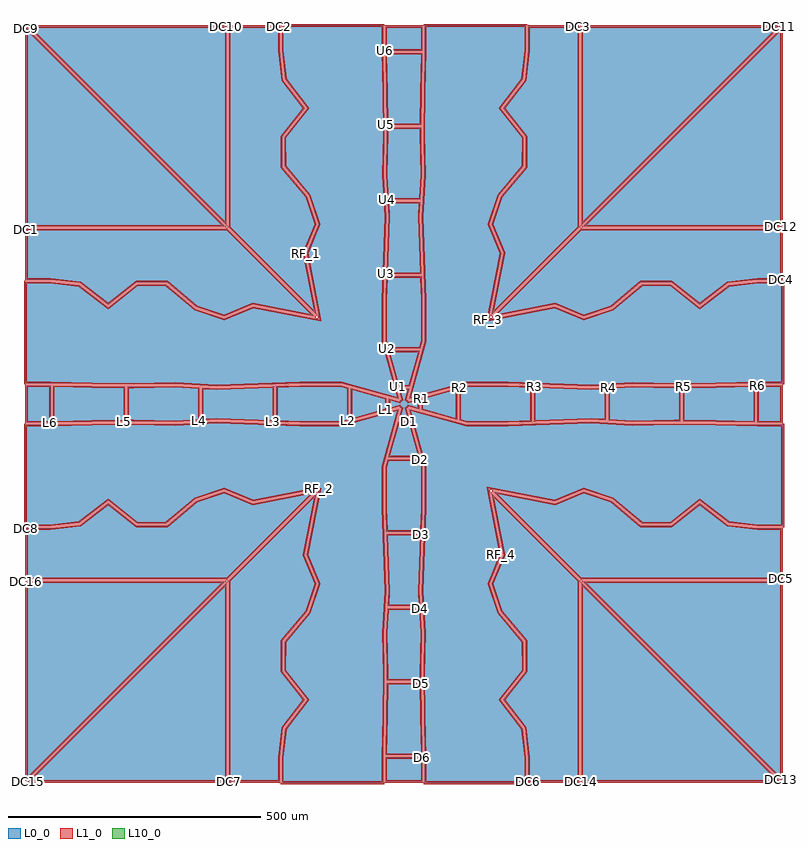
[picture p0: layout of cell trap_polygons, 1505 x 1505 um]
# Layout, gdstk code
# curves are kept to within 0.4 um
import gdstk
lib = gdstk.Library(unit=1e-6, precision=1e-09)
def P(c, l, *ps):  # polygons
    for p in ps: c.add(gdstk.Polygon(p, *l))
L0_0 = (0, 0)
L1_0 = (1, 0)
L10_0 = (10, 0)

trap_polygons = lib.new_cell('trap_polygons')
P(trap_polygons, L0_0, [(-747.5,-351.5),(-355.036,-351.5),(-747.5,-743.964),(-747.5,-351.5)],
  [(-743.964,-747.5),(-351.5,-355.036),(-351.5,-747.5),(-743.964,-747.5)],
  [(351.5,-747.5),(351.5,-355.036),(743.964,-747.5),(351.5,-747.5)],
  [(747.5,-743.964),(355.036,-351.5),(747.5,-351.5),(747.5,-743.964)],
  [(747.5,351.5),(355.036,351.5),(747.5,743.964),(747.5,351.5)],
  [(743.964,747.5),(351.5,355.036),(351.5,747.5),(743.964,747.5)],
  [(-351.5,747.5),(-351.5,355.036),(-743.964,747.5),(-351.5,747.5)],
  [(-747.5,743.964),(-355.036,351.5),(-747.5,351.5),(-747.5,743.964)],
  [(-747.5,-246.5),(-699.71,-246.5),(-640.731,-239.63),(-585.43,-196.951),(-529.805,-241.432),(-468.92,-241.136),(-410.94,-192.501),(-356.299,-173.873),(-299.337,-197.523),(-177.273,-173.737),(-350.036,-346.5),(-747.5,-346.5)],
  [(-346.5,-747.5),(-346.5,-350.036),(-173.737,-177.273),(-197.523,-299.337),(-173.873,-356.299),(-192.501,-410.94),(-241.136,-468.92),(-241.432,-529.805),(-196.951,-585.43),(-239.63,-640.731),(-246.5,-699.71),(-246.5,-747.5)],
  [(246.5,-747.5),(246.5,-699.71),(239.63,-640.731),(196.951,-585.43),(241.432,-529.805),(241.136,-468.92),(192.501,-410.94),(173.873,-356.299),(197.523,-299.337),(173.737,-177.273),(346.5,-350.036),(346.5,-747.5)],
  [(747.5,-346.5),(350.036,-346.5),(177.273,-173.737),(299.337,-197.523),(356.299,-173.873),(410.94,-192.501),(468.92,-241.136),(529.805,-241.432),(585.43,-196.951),(640.731,-239.63),(699.71,-246.5),(747.5,-246.5)],
  [(747.5,246.5),(699.71,246.5),(640.731,239.63),(585.43,196.951),(529.805,241.432),(468.92,241.136),(410.94,192.501),(356.299,173.873),(299.337,197.523),(177.273,173.737),(350.036,346.5),(747.5,346.5)],
  [(346.5,747.5),(346.5,350.036),(173.737,177.273),(197.523,299.337),(173.873,356.299),(192.501,410.94),(241.136,468.92),(241.432,529.805),(196.951,585.43),(239.63,640.731),(246.5,699.71),(246.5,747.5)],
  [(-246.5,747.5),(-246.5,699.71),(-239.63,640.731),(-196.951,585.43),(-241.432,529.805),(-241.136,468.92),(-192.501,410.94),(-173.873,356.299),(-197.523,299.337),(-173.737,177.273),(-346.5,350.036),(-346.5,747.5)],
  [(-747.5,346.5),(-350.036,346.5),(-177.273,173.737),(-299.337,197.523),(-356.299,173.873),(-410.94,192.501),(-468.92,241.136),(-529.805,241.432),(-585.43,196.951),(-640.731,239.63),(-699.71,246.5),(-747.5,246.5)],
  [(-36.5,700),(-36.5,747.5),(36.5,747.5),(36.5,700),(-36.5,700)],
  [(700,36.5),(747.5,36.5),(747.5,-36.5),(700,-36.5),(700,36.5)],
  [(36.5,-700),(36.5,-747.5),(-36.5,-747.5),(-36.5,-700),(36.5,-700)],
  [(-700,-36.5),(-747.5,-36.5),(-747.5,36.5),(-700,36.5),(-700,-36.5)],
  [(-33.917,552.5),(-34.849,617.925),(-36.5,695),(36.5,695),(34.849,617.925),(33.917,552.5),(-33.917,552.5)],
  [(552.5,33.917),(617.925,34.849),(695,36.5),(695,-36.5),(617.925,-34.849),(552.5,-33.917),(552.5,33.917)],
  [(33.917,-552.5),(34.849,-617.925),(36.5,-695),(-36.5,-695),(-34.849,-617.925),(-33.917,-552.5),(33.917,-552.5)],
  [(-552.5,-33.917),(-617.925,-34.849),(-695,-36.5),(-695,36.5),(-617.925,34.849),(-552.5,33.917),(-552.5,-33.917)],
  [(-32.503,405),(-35.298,453.158),(-33.673,535.361),(-33.846,547.5),(33.846,547.5),(33.673,535.361),(35.298,453.158),(32.503,405),(-32.503,405)],
  [(405,32.503),(453.158,35.298),(535.361,33.673),(547.5,33.846),(547.5,-33.846),(535.361,-33.673),(453.158,-35.298),(405,-32.503),(405,32.503)],
  [(32.503,-405),(35.298,-453.158),(33.673,-535.361),(33.846,-547.5),(-33.846,-547.5),(-33.673,-535.361),(-35.298,-453.158),(-32.503,-405),(32.503,-405)],
  [(-405,-32.503),(-453.158,-35.298),(-535.361,-33.673),(-547.5,-33.846),(-547.5,33.846),(-535.361,33.673),(-453.158,35.298),(-405,32.503),(-405,-32.503)],
  [(-34.587,257.5),(-33.444,288.256),(-30.519,370.806),(-32.213,400),(32.213,400),(30.519,370.806),(33.444,288.256),(34.587,257.5),(-34.587,257.5)],
  [(257.5,34.587),(288.256,33.444),(370.806,30.519),(400,32.213),(400,-32.213),(370.806,-30.519),(288.256,-33.444),(257.5,-34.587),(257.5,34.587)],
  [(34.587,-257.5),(33.444,-288.256),(30.519,-370.806),(32.213,-400),(-32.213,-400),(-30.519,-370.806),(-33.444,-288.256),(-34.587,-257.5),(34.587,-257.5)],
  [(-257.5,-34.587),(-288.256,-33.444),(-370.806,-30.519),(-400,-32.213),(-400,32.213),(-370.806,30.519),(-288.256,33.444),(-257.5,34.587),(-257.5,-34.587)],
  [(-32.49,110),(-36.5,124.492),(-36.5,206.032),(-34.773,252.5),(34.773,252.5),(36.5,206.032),(36.5,124.492),(32.49,110),(-32.49,110)],
  [(110,32.49),(124.492,36.5),(206.032,36.5),(252.5,34.773),(252.5,-34.773),(206.032,-36.5),(124.492,-36.5),(110,-32.49),(110,32.49)],
  [(32.49,-110),(36.5,-124.492),(36.5,-206.032),(34.773,-252.5),(-34.773,-252.5),(-36.5,-206.032),(-36.5,-124.492),(-32.49,-110),(32.49,-110)],
  [(-110,-32.49),(-124.492,-36.5),(-206.032,-36.5),(-252.5,-34.773),(-252.5,34.773),(-206.032,36.5),(-124.492,36.5),(-110,32.49),(-110,-32.49)],
  [(-11.734,35),(-31.106,105),(31.106,105),(11.734,35),(-11.734,35)],
  [(35,11.734),(105,31.106),(105,-31.106),(35,-11.734),(35,11.734)],
  [(11.734,-35),(31.106,-105),(-31.106,-105),(-11.734,-35),(11.734,-35)],
  [(-35,-11.734),(-105,-31.106),(-105,31.106),(-35,11.734),(-35,-11.734)],
  [(8.315,-5.556),(4.514,-8.914),(10.35,-30),(-10.35,-30),(-4.514,-8.914),(-7.071,-7.071),(-8.914,-4.514),(-30,-10.35),(-30,10.35),(-8.914,4.514),(-7.071,7.071),(-4.514,8.914),(-10.35,30),(10.35,30),(4.514,8.914),(7.071,7.071),(8.914,4.514),(30,10.35),(30,-10.35),(8.914,-4.514)],
  [(192.327,-298.812),(168.531,-356.125),(188.07,-413.437),(236.144,-470.75),(236.423,-528.062),(190.593,-585.375),(234.824,-642.687),(241.5,-700),(241.5,-750),(41.5,-750),(41.5,-700),(38.674,-535.375),(40.301,-453.062),(35.524,-370.75),(41.5,-206.125),(41.5,-123.812),(10.004,-10.004),(123.812,-41.5),(206.125,-41.5),(370.75,-35.524),(453.062,-40.301),(535.375,-38.674),(700,-41.5),(750,-41.5),(750,-241.5),(700,-241.5),(642.687,-234.824),(585.375,-190.593),(528.062,-236.423),(470.75,-236.144),(413.437,-188.07),(356.125,-168.531),(298.812,-192.327),(166.555,-166.555)],
  [(166.555,166.555),(298.812,192.327),(356.125,168.531),(413.437,188.07),(470.75,236.144),(528.062,236.423),(585.375,190.593),(642.687,234.824),(700,241.5),(750,241.5),(750,41.5),(700,41.5),(535.375,38.674),(453.062,40.301),(370.75,35.524),(206.125,41.5),(123.812,41.5),(10.004,10.004),(41.5,123.812),(41.5,206.125),(35.524,370.75),(40.301,453.062),(38.674,535.375),(41.5,700),(41.5,750),(241.5,750),(241.5,700),(234.824,642.687),(190.593,585.375),(236.423,528.062),(236.144,470.75),(188.07,413.437),(168.531,356.125),(192.327,298.812)],
  [(-166.555,-166.555),(-298.812,-192.327),(-356.125,-168.531),(-413.437,-188.07),(-470.75,-236.144),(-528.062,-236.423),(-585.375,-190.593),(-642.687,-234.824),(-700,-241.5),(-750,-241.5),(-750,-41.5),(-700,-41.5),(-535.375,-38.674),(-453.062,-40.301),(-370.75,-35.524),(-206.125,-41.5),(-123.812,-41.5),(-10.004,-10.004),(-41.5,-123.812),(-41.5,-206.125),(-35.524,-370.75),(-40.301,-453.062),(-38.674,-535.375),(-41.5,-700),(-41.5,-750),(-241.5,-750),(-241.5,-700),(-234.824,-642.687),(-190.593,-585.375),(-236.423,-528.062),(-236.144,-470.75),(-188.07,-413.437),(-168.531,-356.125),(-192.327,-298.812)],
  [(-192.327,298.812),(-168.531,356.125),(-188.07,413.437),(-236.144,470.75),(-236.423,528.062),(-190.593,585.375),(-234.824,642.687),(-241.5,700),(-241.5,750),(-41.5,750),(-41.5,700),(-38.674,535.375),(-40.301,453.062),(-35.524,370.75),(-41.5,206.125),(-41.5,123.812),(-10.004,10.004),(-123.812,41.5),(-206.125,41.5),(-370.75,35.524),(-453.062,40.301),(-535.375,38.674),(-700,41.5),(-750,41.5),(-750,241.5),(-700,241.5),(-642.687,234.824),(-585.375,190.593),(-528.062,236.423),(-470.75,236.144),(-413.437,188.07),(-356.125,168.531),(-298.812,192.327),(-166.555,166.555)])
P(trap_polygons, L1_0, [(-747.5,-349),(-747.5,-354),(-361.071,-354),(-745,-737.929),(-745,-351.5),(-750,-351.5),(-750,-746.464),(-747.5,-747.5),(-351.5,-351.5),(-352.536,-349)],
  [(-745.732,-745.732),(-742.197,-749.268),(-354,-361.071),(-354,-745),(-743.964,-745),(-743.964,-750),(-349,-750),(-349,-352.536),(-351.5,-351.5)],
  [(349,-747.5),(354,-747.5),(354,-361.071),(737.929,-745),(351.5,-745),(351.5,-750),(746.464,-750),(747.5,-747.5),(351.5,-351.5),(349,-352.536)],
  [(745.732,-745.732),(749.268,-742.197),(361.071,-354),(745,-354),(745,-743.964),(750,-743.964),(750,-349),(352.536,-349),(351.5,-351.5)],
  [(747.5,349),(747.5,354),(361.071,354),(745,737.929),(745,351.5),(750,351.5),(750,746.464),(747.5,747.5),(351.5,351.5),(352.536,349)],
  [(745.732,745.732),(742.197,749.268),(354,361.071),(354,745),(743.964,745),(743.964,750),(349,750),(349,352.536),(351.5,351.5)],
  [(-349,747.5),(-354,747.5),(-354,361.071),(-737.929,745),(-351.5,745),(-351.5,750),(-746.464,750),(-747.5,747.5),(-351.5,351.5),(-349,352.536)],
  [(-745.732,745.732),(-749.268,742.197),(-361.071,354),(-745,354),(-745,743.964),(-750,743.964),(-750,349),(-352.536,349),(-351.5,351.5)],
  [(-747.5,-244),(-747.5,-249),(-699.565,-249),(-639.753,-242.033),(-585.457,-200.13),(-530.676,-243.936),(-468.005,-243.631),(-409.691,-194.717),(-356.385,-176.543),(-299.599,-200.121),(-184.828,-177.757),(-351.071,-344),(-745,-344),(-745,-246.5),(-750,-246.5),(-750,-349),(-349,-349),(-173.737,-173.737),(-175.297,-170.805),(-299.075,-194.925),(-356.212,-171.202),(-412.189,-190.286),(-469.835,-238.64),(-528.934,-238.927),(-585.402,-193.772),(-641.709,-237.227),(-699.855,-244)],
  [(-349,-747.5),(-344,-747.5),(-344,-351.071),(-177.757,-184.828),(-200.121,-299.599),(-176.543,-356.385),(-194.717,-409.691),(-243.631,-468.005),(-243.936,-530.676),(-200.13,-585.457),(-242.033,-639.753),(-249,-699.565),(-249,-745),(-346.5,-745),(-346.5,-750),(-244,-750),(-244,-699.855),(-237.227,-641.709),(-193.772,-585.402),(-238.927,-528.934),(-238.64,-469.835),(-190.286,-412.189),(-171.202,-356.212),(-194.925,-299.075),(-170.805,-175.297),(-173.737,-173.737),(-349,-349)],
  [(244,-747.5),(249,-747.5),(249,-699.565),(242.033,-639.753),(200.13,-585.457),(243.936,-530.676),(243.631,-468.005),(194.717,-409.691),(176.543,-356.385),(200.121,-299.599),(177.757,-184.828),(344,-351.071),(344,-745),(246.5,-745),(246.5,-750),(349,-750),(349,-349),(173.737,-173.737),(170.805,-175.297),(194.925,-299.075),(171.202,-356.212),(190.286,-412.189),(238.64,-469.835),(238.927,-528.934),(193.772,-585.402),(237.227,-641.709),(244,-699.855)],
  [(747.5,-349),(747.5,-344),(351.071,-344),(184.828,-177.757),(299.599,-200.121),(356.385,-176.543),(409.691,-194.717),(468.005,-243.631),(530.676,-243.936),(585.457,-200.13),(639.753,-242.033),(699.565,-249),(745,-249),(745,-346.5),(750,-346.5),(750,-244),(699.855,-244),(641.709,-237.227),(585.402,-193.772),(528.934,-238.927),(469.835,-238.64),(412.189,-190.286),(356.212,-171.202),(299.075,-194.925),(175.297,-170.805),(173.737,-173.737),(349,-349)],
  [(747.5,244),(747.5,249),(699.565,249),(639.753,242.033),(585.457,200.13),(530.676,243.936),(468.005,243.631),(409.691,194.717),(356.385,176.543),(299.599,200.121),(184.828,177.757),(351.071,344),(745,344),(745,246.5),(750,246.5),(750,349),(349,349),(173.737,173.737),(175.297,170.805),(299.075,194.925),(356.212,171.202),(412.189,190.286),(469.835,238.64),(528.934,238.927),(585.402,193.772),(641.709,237.227),(699.855,244)],
  [(349,747.5),(344,747.5),(344,351.071),(177.757,184.828),(200.121,299.599),(176.543,356.385),(194.717,409.691),(243.631,468.005),(243.936,530.676),(200.13,585.457),(242.033,639.753),(249,699.565),(249,745),(346.5,745),(346.5,750),(244,750),(244,699.855),(237.227,641.709),(193.772,585.402),(238.927,528.934),(238.64,469.835),(190.286,412.189),(171.202,356.212),(194.925,299.075),(170.805,175.297),(173.737,173.737),(349,349)],
  [(-244,747.5),(-249,747.5),(-249,699.565),(-242.033,639.753),(-200.13,585.457),(-243.936,530.676),(-243.631,468.005),(-194.717,409.691),(-176.543,356.385),(-200.121,299.599),(-177.757,184.828),(-344,351.071),(-344,745),(-246.5,745),(-246.5,750),(-349,750),(-349,349),(-173.737,173.737),(-170.805,175.297),(-194.925,299.075),(-171.202,356.212),(-190.286,412.189),(-238.64,469.835),(-238.927,528.934),(-193.772,585.402),(-237.227,641.709),(-244,699.855)],
  [(-747.5,349),(-747.5,344),(-351.071,344),(-184.828,177.757),(-299.599,200.121),(-356.385,176.543),(-409.691,194.717),(-468.005,243.631),(-530.676,243.936),(-585.457,200.13),(-639.753,242.033),(-699.565,249),(-745,249),(-745,346.5),(-750,346.5),(-750,244),(-699.855,244),(-641.709,237.227),(-585.402,193.772),(-528.934,238.927),(-469.835,238.64),(-412.189,190.286),(-356.212,171.202),(-299.075,194.925),(-175.297,170.805),(-173.737,173.737),(-349,349)],
  [(-39,700),(-34,700),(-34,745),(34,745),(34,702.5),(-36.5,702.5),(-36.5,697.5),(39,697.5),(39,750),(-39,750)],
  [(700,39),(700,34),(745,34),(745,-34),(702.5,-34),(702.5,36.5),(697.5,36.5),(697.5,-39),(750,-39),(750,39)],
  [(39,-700),(34,-700),(34,-745),(-34,-745),(-34,-702.5),(36.5,-702.5),(36.5,-697.5),(-39,-697.5),(-39,-750),(39,-750)],
  [(-700,-39),(-700,-34),(-745,-34),(-745,34),(-702.5,34),(-702.5,-36.5),(-697.5,-36.5),(-697.5,39),(-750,39),(-750,-39)],
  [(-36.417,552.464),(-31.418,552.536),(-33.946,692.5),(33.946,692.5),(31.453,555),(-33.917,555),(-33.917,550),(36.382,550),(39,697.5),(-39.053,697.446)],
  [(552.464,36.417),(552.536,31.418),(692.5,33.946),(692.5,-33.946),(555,-31.453),(555,33.917),(550,33.917),(550,-36.382),(697.5,-39),(697.446,39.053)],
  [(36.417,-552.464),(31.418,-552.536),(33.946,-692.5),(-33.946,-692.5),(-31.453,-555),(33.917,-555),(33.917,-550),(-36.382,-550),(-39,-697.5),(39.053,-697.446)],
  [(-552.464,-36.417),(-552.536,-31.418),(-692.5,-33.946),(-692.5,33.946),(-555,31.453),(-555,-33.917),(-550,-33.917),(-550,36.382),(-697.5,39),(-697.446,-39.053)],
  [(-34.999,404.855),(-30.008,405.145),(-32.797,453.206),(-31.31,545),(31.31,545),(32.797,453.206),(30.144,407.5),(-32.503,407.5),(-32.503,402.5),(34.862,402.5),(37.8,453.11),(36.346,550),(-36.381,549.964),(-36.173,535.368),(-37.8,453.11)],
  [(404.855,34.999),(405.145,30.008),(453.206,32.797),(545,31.31),(545,-31.31),(453.206,-32.797),(407.5,-30.144),(407.5,32.503),(402.5,32.503),(402.5,-34.862),(453.11,-37.8),(550,-36.346),(549.964,36.381),(535.368,36.173),(453.11,37.8)],
  [(34.999,-404.855),(30.008,-405.145),(32.797,-453.206),(31.31,-545),(-31.31,-545),(-32.797,-453.206),(-30.144,-407.5),(32.503,-407.5),(32.503,-402.5),(-34.862,-402.5),(-37.8,-453.11),(-36.346,-550),(36.381,-549.964),(36.173,-535.368),(37.8,-453.11)],
  [(-404.855,-34.999),(-405.145,-30.008),(-453.206,-32.797),(-545,-31.31),(-545,31.31),(-453.206,32.797),(-407.5,30.144),(-407.5,-32.503),(-402.5,-32.503),(-402.5,34.862),(-453.11,37.8),(-550,36.346),(-549.964,-36.381),(-535.368,-36.173),(-453.11,-37.8)],
  [(-37.085,257.593),(-32.089,257.407),(-28.016,370.835),(-29.564,397.5),(29.564,397.5),(28.016,370.835),(31.992,260),(-34.587,260),(-34.587,255),(37.178,255.095),(33.022,370.778),(34.713,402.5),(-34.854,402.351),(-33.022,370.778)],
  [(257.593,37.085),(257.407,32.089),(370.835,28.016),(397.5,29.564),(397.5,-29.564),(370.835,-28.016),(260,-31.992),(260,34.587),(255,34.587),(255.095,-37.178),(370.778,-33.022),(402.5,-34.713),(402.351,34.854),(370.778,33.022)],
  [(37.085,-257.593),(32.089,-257.407),(28.016,-370.835),(29.564,-397.5),(-29.564,-397.5),(-28.016,-370.835),(-31.992,-260),(34.587,-260),(34.587,-255),(-37.178,-255.095),(-33.022,-370.778),(-34.713,-402.5),(34.854,-402.351),(33.022,-370.778)],
  [(-257.593,-37.085),(-257.407,-32.089),(-370.835,-28.016),(-397.5,-29.564),(-397.5,29.564),(-370.835,28.016),(-260,31.992),(-260,-34.587),(-255,-34.587),(-255.095,37.178),(-370.778,33.022),(-402.5,34.713),(-402.351,-34.854),(-370.778,-33.022)],
  [(-34.899,109.333),(-30.08,110.667),(-34,124.831),(-34,205.986),(-32.364,250),(32.364,250),(34,205.986),(34,124.831),(30.587,112.5),(-32.49,112.5),(-32.49,107.5),(34.392,107.5),(39,124.152),(39,206.079),(37.182,255),(-37.182,255),(-39,206.079),(-39,124.152)],
  [(109.333,34.899),(110.667,30.08),(124.831,34),(205.986,34),(250,32.364),(250,-32.364),(205.986,-34),(124.831,-34),(112.5,-30.587),(112.5,32.49),(107.5,32.49),(107.5,-34.392),(124.152,-39),(206.079,-39),(255,-37.182),(255,37.182),(206.079,39),(124.152,39)],
  [(34.899,-109.333),(30.08,-110.667),(34,-124.831),(34,-205.986),(32.364,-250),(-32.364,-250),(-34,-205.986),(-34,-124.831),(-30.587,-112.5),(32.49,-112.5),(32.49,-107.5),(-34.392,-107.5),(-39,-124.152),(-39,-206.079),(-37.182,-255),(37.182,-255),(39,-206.079),(39,-124.152)],
  [(-109.333,-34.899),(-110.667,-30.08),(-124.831,-34),(-205.986,-34),(-250,-32.364),(-250,32.364),(-205.986,34),(-124.831,34),(-112.5,30.587),(-112.5,-32.49),(-107.5,-32.49),(-107.5,34.392),(-124.152,39),(-206.079,39),(-255,37.182),(-255,-37.182),(-206.079,-39),(-124.152,-39)],
  [(-14.143,34.333),(-9.324,35.667),(-27.82,102.5),(27.82,102.5),(9.832,37.5),(-11.734,37.5),(-11.734,32.5),(13.636,32.5),(34.182,106.743),(33.606,107.5),(-33.606,107.5),(-34.182,106.743)],
  [(34.333,14.143),(35.667,9.324),(102.5,27.82),(102.5,-27.82),(37.5,-9.832),(37.5,11.734),(32.5,11.734),(32.5,-13.636),(106.743,-34.182),(107.5,-33.606),(107.5,33.606),(106.743,34.182)],
  [(14.143,-34.333),(9.324,-35.667),(27.82,-102.5),(-27.82,-102.5),(-9.832,-37.5),(11.734,-37.5),(11.734,-32.5),(-13.636,-32.5),(-34.182,-106.743),(-33.606,-107.5),(33.606,-107.5),(34.182,-106.743)],
  [(-34.333,-14.143),(-35.667,-9.324),(-102.5,-27.82),(-102.5,27.82),(-37.5,9.832),(-37.5,-11.734),(-32.5,-11.734),(-32.5,13.636),(-106.743,34.182),(-107.5,33.606),(-107.5,-33.606),(-106.743,-34.182)],
  [(10.323,-7.045),(6.307,-4.066),(4.165,-6.234),(1.544,-7.553),(7.064,-27.5),(-7.064,-27.5),(-1.544,-7.553),(-5.301,-5.301),(-7.553,-1.544),(-27.5,-7.064),(-27.5,7.064),(-7.553,1.544),(-5.301,5.301),(-1.544,7.553),(-7.064,27.5),(7.064,27.5),(1.544,7.553),(5.301,5.301),(7.553,1.544),(27.5,7.064),(27.5,-7.064),(7.553,-1.544),(6.17,-4.27),(10.459,-6.841),(11.027,-5.894),(10.274,-7.485),(31.743,-13.426),(32.5,-12.85),(32.5,12.85),(31.743,13.426),(10.274,7.485),(11.027,5.894),(8.841,8.841),(5.894,11.027),(7.485,10.274),(13.426,31.743),(12.85,32.5),(-12.85,32.5),(-13.426,31.743),(-7.485,10.274),(-5.894,11.027),(-8.841,8.841),(-11.027,5.894),(-10.274,7.485),(-31.743,13.426),(-32.5,12.85),(-32.5,-12.85),(-31.743,-13.426),(-10.274,-7.485),(-11.027,-5.894),(-8.841,-8.841),(-5.894,-11.027),(-7.485,-10.274),(-13.426,-31.743),(-12.85,-32.5),(12.85,-32.5),(13.426,-31.743),(7.485,-10.274),(5.894,-11.027)],
  [(194.636,-299.771),(190.018,-297.854),(165.86,-356.038),(185.855,-414.686),(233.649,-471.665),(233.919,-527.191),(187.414,-585.348),(232.421,-643.666),(239,-700.145),(239,-747.5),(44,-747.5),(44,-699.975),(41.174,-535.382),(42.802,-453.015),(38.027,-370.722),(44,-206.171),(44,-123.473),(13.591,-13.591),(123.473,-44),(206.171,-44),(370.722,-38.027),(453.015,-42.802),(535.382,-41.174),(699.975,-44),(747.5,-44),(747.5,-239),(700.145,-239),(643.666,-232.421),(585.348,-187.414),(527.191,-233.919),(471.665,-233.649),(414.686,-185.855),(356.038,-165.86),(298.55,-189.729),(164.579,-163.623),(163.623,-164.579),(189.873,-299.291),(194.781,-298.334),(169.718,-169.718),(299.075,-194.925),(356.212,-171.202),(412.189,-190.286),(469.835,-238.64),(528.934,-238.927),(585.402,-193.772),(641.709,-237.227),(699.855,-244),(752.5,-244),(752.5,-39),(700.025,-39),(535.368,-36.173),(453.11,-37.8),(370.778,-33.022),(206.079,-39),(124.152,-39),(8.262,-6.928),(6.928,-8.262),(39,-124.152),(39,-206.079),(33.022,-370.778),(37.8,-453.11),(36.173,-535.368),(39,-700.025),(39,-752.5),(244,-752.5),(244,-699.855),(237.227,-641.709),(193.772,-585.402),(238.927,-528.934),(238.64,-469.835),(190.286,-412.189),(171.202,-356.212)],
  [(166.077,169.009),(167.033,164.101),(298.55,189.729),(356.038,165.86),(414.686,185.855),(471.665,233.649),(527.191,233.919),(585.348,187.414),(643.666,232.421),(700.145,239),(747.5,239),(747.5,44),(699.975,44),(535.382,41.174),(453.015,42.802),(370.722,38.027),(206.171,44),(123.473,44),(13.591,13.591),(44,123.473),(44,206.171),(38.027,370.722),(42.802,453.015),(41.174,535.382),(44,699.975),(44,747.5),(239,747.5),(239,700.145),(232.421,643.666),(187.414,585.348),(233.919,527.191),(233.649,471.665),(185.855,414.686),(165.86,356.038),(189.729,298.55),(164.101,167.033),(169.009,166.077),(194.925,299.075),(171.202,356.212),(190.286,412.189),(238.64,469.835),(238.927,528.934),(193.772,585.402),(237.227,641.709),(244,699.855),(244,752.5),(39,752.5),(39,700.025),(36.173,535.368),(37.8,453.11),(33.022,370.778),(39,206.079),(39,124.152),(6.928,8.262),(8.262,6.928),(124.152,39),(206.079,39),(370.778,33.022),(453.11,37.8),(535.368,36.173),(700.025,39),(752.5,39),(752.5,244),(699.855,244),(641.709,237.227),(585.402,193.772),(528.934,238.927),(469.835,238.64),(412.189,190.286),(356.212,171.202),(299.075,194.925)],
  [(-166.077,-169.009),(-167.033,-164.101),(-298.55,-189.729),(-356.038,-165.86),(-414.686,-185.855),(-471.665,-233.649),(-527.191,-233.919),(-585.348,-187.414),(-643.666,-232.421),(-700.145,-239),(-747.5,-239),(-747.5,-44),(-699.975,-44),(-535.382,-41.174),(-453.015,-42.802),(-370.722,-38.027),(-206.171,-44),(-123.473,-44),(-13.591,-13.591),(-44,-123.473),(-44,-206.171),(-38.027,-370.722),(-42.802,-453.015),(-41.174,-535.382),(-44,-699.975),(-44,-747.5),(-239,-747.5),(-239,-700.145),(-232.421,-643.666),(-187.414,-585.348),(-233.919,-527.191),(-233.649,-471.665),(-185.855,-414.686),(-165.86,-356.038),(-189.729,-298.55),(-164.101,-167.033),(-169.009,-166.077),(-194.925,-299.075),(-171.202,-356.212),(-190.286,-412.189),(-238.64,-469.835),(-238.927,-528.934),(-193.772,-585.402),(-237.227,-641.709),(-244,-699.855),(-244,-752.5),(-39,-752.5),(-39,-700.025),(-36.173,-535.368),(-37.8,-453.11),(-33.022,-370.778),(-39,-206.079),(-39,-124.152),(-6.928,-8.262),(-8.262,-6.928),(-124.152,-39),(-206.079,-39),(-370.778,-33.022),(-453.11,-37.8),(-535.368,-36.173),(-700.025,-39),(-752.5,-39),(-752.5,-244),(-699.855,-244),(-641.709,-237.227),(-585.402,-193.772),(-528.934,-238.927),(-469.835,-238.64),(-412.189,-190.286),(-356.212,-171.202),(-299.075,-194.925)],
  [(-194.636,299.771),(-190.018,297.854),(-165.86,356.038),(-185.855,414.686),(-233.649,471.665),(-233.919,527.191),(-187.414,585.348),(-232.421,643.666),(-239,700.145),(-239,747.5),(-44,747.5),(-44,699.975),(-41.174,535.382),(-42.802,453.015),(-38.027,370.722),(-44,206.171),(-44,123.473),(-13.591,13.591),(-123.473,44),(-206.171,44),(-370.722,38.027),(-453.015,42.802),(-535.382,41.174),(-699.975,44),(-747.5,44),(-747.5,239),(-700.145,239),(-643.666,232.421),(-585.348,187.414),(-527.191,233.919),(-471.665,233.649),(-414.686,185.855),(-356.038,165.86),(-298.55,189.729),(-164.579,163.623),(-163.623,164.579),(-189.873,299.291),(-194.781,298.334),(-169.718,169.718),(-299.075,194.925),(-356.212,171.202),(-412.189,190.286),(-469.835,238.64),(-528.934,238.927),(-585.402,193.772),(-641.709,237.227),(-699.855,244),(-752.5,244),(-752.5,39),(-700.025,39),(-535.368,36.173),(-453.11,37.8),(-370.778,33.022),(-206.079,39),(-124.152,39),(-8.262,6.928),(-6.928,8.262),(-39,124.152),(-39,206.079),(-33.022,370.778),(-37.8,453.11),(-36.173,535.368),(-39,700.025),(-39,752.5),(-244,752.5),(-244,699.855),(-237.227,641.709),(-193.772,585.402),(-238.927,528.934),(-238.64,469.835),(-190.286,412.189),(-171.202,356.212)])
P(trap_polygons, L10_0, [(0,0),(0,0),(0,0),(0,0)])
trap_polygons.add(gdstk.Label('DC16', (-747.5,-351.5), layer=2, texttype=0))
trap_polygons.add(gdstk.Label('DC15', (-743.964,-747.5), layer=2, texttype=0))
trap_polygons.add(gdstk.Label('DC14', (351.5,-747.5), layer=2, texttype=0))
trap_polygons.add(gdstk.Label('DC13', (747.5,-743.964), layer=2, texttype=0))
trap_polygons.add(gdstk.Label('DC12', (747.5,351.5), layer=2, texttype=0))
trap_polygons.add(gdstk.Label('DC11', (743.964,747.5), layer=2, texttype=0))
trap_polygons.add(gdstk.Label('DC10', (-351.5,747.5), layer=2, texttype=0))
trap_polygons.add(gdstk.Label('DC9', (-747.5,743.964), layer=2, texttype=0))
trap_polygons.add(gdstk.Label('DC8', (-747.5,-246.5), layer=2, texttype=0))
trap_polygons.add(gdstk.Label('DC7', (-346.5,-747.5), layer=2, texttype=0))
trap_polygons.add(gdstk.Label('DC6', (246.5,-747.5), layer=2, texttype=0))
trap_polygons.add(gdstk.Label('DC5', (747.5,-346.5), layer=2, texttype=0))
trap_polygons.add(gdstk.Label('DC4', (747.5,246.5), layer=2, texttype=0))
trap_polygons.add(gdstk.Label('DC3', (346.5,747.5), layer=2, texttype=0))
trap_polygons.add(gdstk.Label('DC2', (-246.5,747.5), layer=2, texttype=0))
trap_polygons.add(gdstk.Label('DC1', (-747.5,346.5), layer=2, texttype=0))
trap_polygons.add(gdstk.Label('U6', (-36.5,700), layer=2, texttype=0))
trap_polygons.add(gdstk.Label('R6', (700,36.5), layer=2, texttype=0))
trap_polygons.add(gdstk.Label('D6', (36.5,-700), layer=2, texttype=0))
trap_polygons.add(gdstk.Label('L6', (-700,-36.5), layer=2, texttype=0))
trap_polygons.add(gdstk.Label('U5', (-33.917,552.5), layer=2, texttype=0))
trap_polygons.add(gdstk.Label('R5', (552.5,33.917), layer=2, texttype=0))
trap_polygons.add(gdstk.Label('D5', (33.917,-552.5), layer=2, texttype=0))
trap_polygons.add(gdstk.Label('L5', (-552.5,-33.917), layer=2, texttype=0))
trap_polygons.add(gdstk.Label('U4', (-32.503,405), layer=2, texttype=0))
trap_polygons.add(gdstk.Label('R4', (405,32.503), layer=2, texttype=0))
trap_polygons.add(gdstk.Label('D4', (32.503,-405), layer=2, texttype=0))
trap_polygons.add(gdstk.Label('L4', (-405,-32.503), layer=2, texttype=0))
trap_polygons.add(gdstk.Label('U3', (-34.587,257.5), layer=2, texttype=0))
trap_polygons.add(gdstk.Label('R3', (257.5,34.587), layer=2, texttype=0))
trap_polygons.add(gdstk.Label('D3', (34.587,-257.5), layer=2, texttype=0))
trap_polygons.add(gdstk.Label('L3', (-257.5,-34.587), layer=2, texttype=0))
trap_polygons.add(gdstk.Label('U2', (-32.49,110), layer=2, texttype=0))
trap_polygons.add(gdstk.Label('R2', (110,32.49), layer=2, texttype=0))
trap_polygons.add(gdstk.Label('D2', (32.49,-110), layer=2, texttype=0))
trap_polygons.add(gdstk.Label('L2', (-110,-32.49), layer=2, texttype=0))
trap_polygons.add(gdstk.Label('U1', (-11.734,35), layer=2, texttype=0))
trap_polygons.add(gdstk.Label('R1', (35,11.734), layer=2, texttype=0))
trap_polygons.add(gdstk.Label('D1', (11.734,-35), layer=2, texttype=0))
trap_polygons.add(gdstk.Label('L1', (-35,-11.734), layer=2, texttype=0))
trap_polygons.add(gdstk.Label('C', (8.315,-5.556), layer=2, texttype=0))
trap_polygons.add(gdstk.Label('RF_4', (192.327,-298.812), layer=2, texttype=0))
trap_polygons.add(gdstk.Label('RF_3', (166.555,166.555), layer=2, texttype=0))
trap_polygons.add(gdstk.Label('RF_2', (-166.555,-166.555), layer=2, texttype=0))
trap_polygons.add(gdstk.Label('RF_1', (-192.327,298.812), layer=2, texttype=0))

lib.write_gds('trap_polygons.gds')
